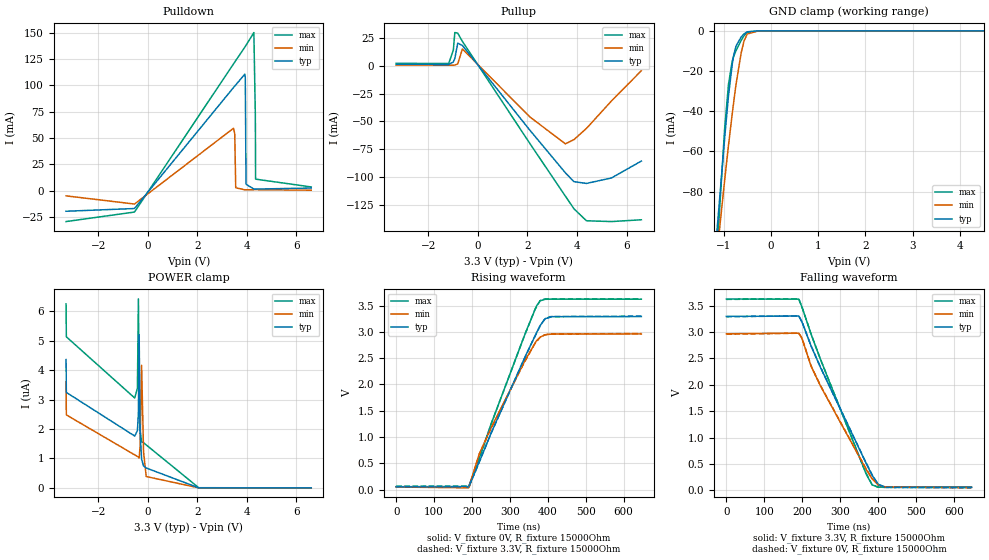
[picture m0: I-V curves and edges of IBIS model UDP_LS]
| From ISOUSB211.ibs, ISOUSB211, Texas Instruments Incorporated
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[Model]   UDP_LS
Model_type   I/O
Polarity   Non-Inverting
Enable   Active-Low
Vinl = 0.8
Vinh = 2
Vmeas = 1.65
Vref = 1.65
Cref = 7pF
Rref = 15000
|   typ   min   max
C_comp   8pF   5pF   10pF
[Voltage Range]   3.3   2.97   3.63
[Temperature Range]   27   150   -40
[Pullup Reference]   3.3   2.97   3.63
[Pulldown Reference]   -0   -0   -0
[Power Clamp Reference]   3.3   2.97   3.63
[GND Clamp Reference]   0   0   0
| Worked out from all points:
|   slope of the pulldown table from 0 to 0.495 V, typ, clamps not added: 33.7 ohm
|   slope of the pullup table from 0 to 0.495 V, typ, clamps not added: 35.8 ohm
|   GND clamp passes 1 mA (typ) near -0.54 V on its own axis
|   falling waveform, V_fixture 3.3V, R_fixture 15000Ohm: 20-80 % time 127ns typ, 128ns min, 116ns max; typ from 3.3 V to 0.057 V
|   rising waveform, V_fixture 0V, R_fixture 15000Ohm: 20-80 % time 119ns typ, 117ns min, 110ns max; typ from 0.05 V to 3.29 V
|   rising waveform, V_fixture 3.3V, R_fixture 15000Ohm: 20-80 % time 119ns typ, 118ns min, 110ns max; typ from 0.057 V to 3.3 V
|   falling waveform, V_fixture 0V, R_fixture 15000Ohm: 20-80 % time 127ns typ, 128ns min, 117ns max; typ from 3.29 V to 0.05 V
[Pulldown]
|   Voltage   I(typ)   I(min)   I(max)
-3.3V     -19.54mA   -4.929mA   -29.33mA
-537.9mV  -16.94mA   -12.7mA    -20.3mA
3.462V    97.95mA    59.28mA    120.4mA
3.511V    99.28mA    54.08mA    122.1mA
3.551V    100.4mA    2.78mA     123.5mA
3.917V    110.6mA    791.1uA    136.2mA
3.937V    107.2mA    798uA      136.9mA
3.967V    6.132mA    808.4uA    138mA
4.283V    1.558mA    916.9uA    150.1mA
4.343V    1.509mA    936.8uA    70.94mA
4.353V    1.513mA    940.1uA    10.95mA
6.6V      2.508mA    452.9uA    3.524mA
[GND Clamp]
|   Voltage   I(typ)   I(min)   I(max)
-3.3V     -1.286A    -1.121A    -1.579A
-1.3V     -145.3mA   -147.2mA   -170.6mA
-973.5mV  -52.59mA   -73.66mA   -47.68mA
-894.3mV  -32.06mA   -56.81mA   -26.49mA
-815.1mV  -16.5mA    -41.06mA   -14.88mA
-785.4mV  -12.23mA   -35.46mA   -12.65mA
-735.9mV  -7.575mA   -26.62mA   -9.853mA
-627mV    -3.033mA   -10.97mA   -4.745mA
-567.6mV  -1.539mA   -5.066mA   -2.489mA
-498.3mV  -471.8uA   -1.571mA   -746.6uA
-260.7mV  0A         -5.306uA   0A
6.6V      0A         0A         0A
[Pullup]
|   Voltage   I(typ)   I(min)   I(max)
-3.3V     1.142mA    462.8uA    2.096mA
-1.181V   1.061mA    442.2uA    1.943mA
-993.3mV  3.404mA    441.8uA    13.88mA
-933.9mV  6.371mA    532.5uA    29.69mA
-815.1mV  20.2mA     1.602mA    29.2mA
-627mV    18.13mA    15.01mA    21.78mA
2.095V    -57.8mA    -45.93mA   -69.71mA
3.531V    -96.08mA   -70.07mA   -117mA
3.877V    -104mA     -66.31mA   -128.3mA
4.382V    -105.6mA   -56.28mA   -139.1mA
5.392V    -100.7mA   -31.65mA   -139.8mA
6.6V      -85.53mA   -4.484mA   -138.2mA
[POWER Clamp]
|   Voltage   I(typ)   I(min)   I(max)
-3.3V     4.356uA    3.599uA    6.246uA
-3.29V    3.241uA    2.478uA    5.13uA
-528mV    1.759uA    1.119uA    3.051uA
-419.1mV  1.943uA    1.069uA    3.389uA
-379.5mV  2.53uA     1.044uA    6.418uA
-349.8mV  5.208uA    1.013uA    3.192uA
-310.2mV  1.899uA    1.42uA     1.946uA
-250.8mV  973.2nA    4.16uA     1.567uA
-171.6mV  741.5nA    1.215uA    1.531uA
-62.7mV   674.3nA    384.4nA    1.457uA
2.056V    0A         0A         4.459nA
6.6V      0A         0A         0A
[Ramp]
R_load = 15000
|   typ   min   max
dV/dt_r   1.94404/1.18803e-07   1.74728/1.17376e-07   2.13944/1.09801e-07
dV/dt_f   1.94431/1.26859e-07   1.74734/1.27745e-07   2.13971/1.1642e-07
[Falling Waveform]
V_fixture = 3.3V
V_fixture_min = 2.97V
V_fixture_max = 3.63V
R_fixture = 15000Ohm
C_fixture = 0F
|   Time   V(typ)   V(min)   V(max)
0s        3.298V     2.968V     3.627V
191.1ns   3.304V     2.98V      3.625V
199.7ns   3.189V     2.877V     3.472V
223.7ns   2.734V     2.351V     2.958V
248ns     2.335V     1.983V     2.49V
369.6ns   501mV      386.8mV    297.9mV
384.7ns   285.7mV    216.3mV    103.3mV
400.7ns   112.8mV    101.1mV    61.56mV
419.8ns   59.09mV    64.55mV    61.44mV
646.7ns   57.28mV    56mV       61.04mV
[Rising Waveform]
V_fixture = 0V
V_fixture_min = 0V
V_fixture_max = 0V
R_fixture = 15000Ohm
C_fixture = 0F
|   Time   V(typ)   V(min)   V(max)
0s        49.91mV    47.52mV    54.29mV
191.1ns   46.69mV    31.65mV    55.44mV
219ns     523.2mV    674.9mV    589.8mV
249.7ns   1.064V     1.165V     1.233V
341.4ns   2.547V     2.475V     2.986V
369.6ns   2.974V     2.825V     3.485V
379.6ns   3.119V     2.899V     3.591V
393.2ns   3.251V     2.945V     3.619V
411.8ns   3.289V     2.958V     3.621V
646.7ns   3.29V      2.96V      3.62V
[Rising Waveform]
V_fixture = 3.3V
V_fixture_min = 2.97V
V_fixture_max = 3.63V
R_fixture = 15000Ohm
C_fixture = 0F
|   Time   V(typ)   V(min)   V(max)
0s        57.28mV    56mV       61.04mV
192.3ns   59.23mV    43.25mV    63.05mV
219ns     518.2mV    668.7mV    587.9mV
249.7ns   1.058V     1.156V     1.232V
334.3ns   2.431V     2.369V     2.854V
365.8ns   2.911V     2.776V     3.42V
379.6ns   3.113V     2.894V     3.592V
391ns     3.235V     2.939V     3.625V
405.6ns   3.289V     2.958V     3.626V
646.7ns   3.298V     2.968V     3.627V
[Falling Waveform]
|Gnd
V_fixture = 0V
V_fixture_min = 0V
V_fixture_max = 0V
R_fixture = 15000Ohm
C_fixture = 0F
|   Time   V(typ)   V(min)   V(max)
0s        3.29V      2.96V      3.62V
191.1ns   3.308V     2.979V     3.63V
199.7ns   3.195V     2.882V     3.474V
223.7ns   2.737V     2.357V     2.96V
248ns     2.342V     1.992V     2.492V
365.8ns   564.5mV    444.8mV    366mV
384.7ns   290.9mV    224.8mV    103.8mV
400.7ns   115.6mV    105.6mV    59.55mV
419.8ns   55.91mV    62.81mV    55.52mV
646.7ns   49.91mV    47.52mV    54.29mV
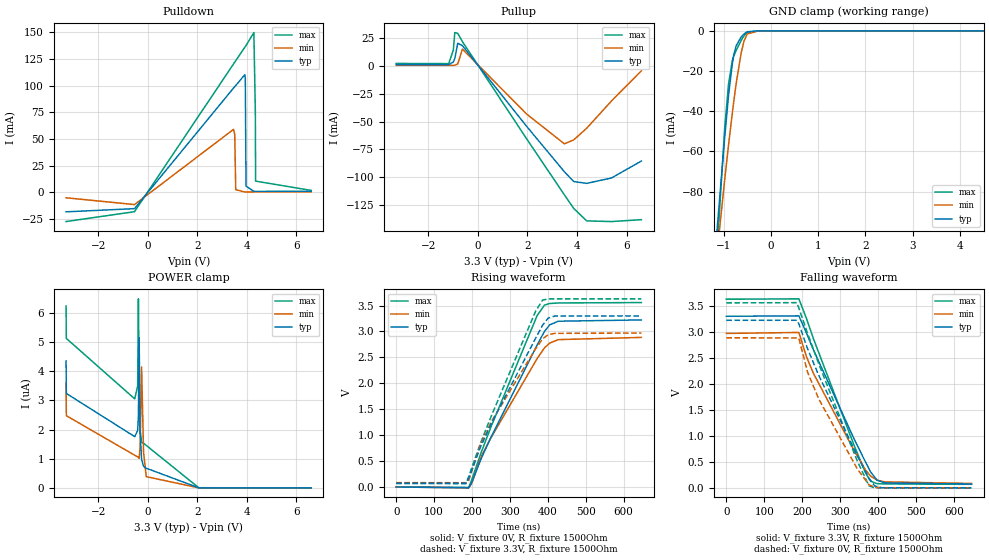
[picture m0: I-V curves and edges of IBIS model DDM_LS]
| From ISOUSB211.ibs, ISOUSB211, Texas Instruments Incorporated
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[Model]   DDM_LS
Model_type   I/O
Polarity   Non-Inverting
Enable   Active-Low
Vinl = 0.8
Vinh = 2
Vmeas = 1.65
Vref = 1.65
Cref = 7pF
Rref = 15000
|   typ   min   max
C_comp   8pF   5pF   10pF
[Voltage Range]   3.3   2.97   3.63
[Temperature Range]   27   150   -40
[Pullup Reference]   3.3   2.97   3.63
[Pulldown Reference]   -0   0   -0
[Power Clamp Reference]   3.3   2.97   3.63
[GND Clamp Reference]   0   0   0
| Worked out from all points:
|   slope of the pulldown table from 0 to 0.495 V, typ, clamps not added: 34.2 ohm
|   slope of the pullup table from 0 to 0.495 V, typ, clamps not added: 35.8 ohm
|   GND clamp passes 1 mA (typ) near -0.54 V on its own axis
|   falling waveform, V_fixture 3.3V, R_fixture 1500Ohm: 20-80 % time 122ns typ, 123ns min, 112ns max; typ from 3.3 V to 0.073 V
|   rising waveform, V_fixture 0V, R_fixture 1500Ohm: 20-80 % time 130ns typ, 134ns min, 118ns max; typ from 0 V to 3.22 V
|   rising waveform, V_fixture 3.3V, R_fixture 1500Ohm: 20-80 % time 133ns typ, 130ns min, 121ns max; typ from 0.073 V to 3.3 V
|   falling waveform, V_fixture 0V, R_fixture 1500Ohm: 20-80 % time 124ns typ, 118ns min, 114ns max; typ from 3.22 V to 0 V
[Pulldown]
|   Voltage   I(typ)   I(min)   I(max)
-3.3V     -18.2mA    -5.021mA   -27.31mA
-537.9mV  -15.2mA    -11.4mA    -18.05mA
3.462V    97.83mA    59.09mA    120.4mA
3.511V    99.15mA    54.21mA    122.1mA
3.551V    100.2mA    2.553mA    123.5mA
3.917V    110.3mA    416.7uA    136mA
3.937V    107.1mA    416.7uA    136.7mA
3.967V    5.835mA    416.7uA    137.7mA
4.283V    1.082mA    416.8uA    149.8mA
4.343V    991.9uA    416.8uA    75.26mA
4.353V    991.9uA    416.8uA    10.57mA
6.6V      1.045mA    453uA      1.865mA
[GND Clamp]
|   Voltage   I(typ)   I(min)   I(max)
-3.3V     -1.286A    -1.12A     -1.579A
-1.3V     -145.3mA   -147.2mA   -170.6mA
-973.5mV  -52.59mA   -73.66mA   -47.69mA
-894.3mV  -32.06mA   -56.82mA   -26.49mA
-815.1mV  -16.5mA    -41.06mA   -14.88mA
-785.4mV  -12.23mA   -35.46mA   -12.65mA
-735.9mV  -7.575mA   -26.62mA   -9.854mA
-627mV    -3.033mA   -10.97mA   -4.745mA
-567.6mV  -1.539mA   -5.066mA   -2.489mA
-498.3mV  -471.8uA   -1.572mA   -746.7uA
-260.7mV  0A         -5.306uA   0A
6.6V      0A         0A         0A
[Pullup]
|   Voltage   I(typ)   I(min)   I(max)
-3.3V     1.143mA    463.2uA    2.098mA
-1.181V   1.062mA    442.5uA    1.976mA
-993.3mV  3.479mA    442.1uA    14.08mA
-933.9mV  6.461mA    534.8uA    29.84mA
-815.1mV  20.25mA    1.633mA    29.15mA
-627mV    18.1mA     14.99mA    21.73mA
1.957V    -54.06mA   -43.1mA    -65.18mA
3.491V    -95.07mA   -70.04mA   -115.8mA
3.868V    -103.9mA   -66.47mA   -128mA
4.392V    -105.5mA   -56.05mA   -139.2mA
5.392V    -100.7mA   -31.61mA   -139.8mA
6.6V      -85.45mA   -4.491mA   -138.1mA
[POWER Clamp]
|   Voltage   I(typ)   I(min)   I(max)
-3.3V     4.356uA    3.599uA    6.245uA
-3.29V    3.24uA     2.477uA    5.129uA
-528mV    1.757uA    1.119uA    3.054uA
-409.2mV  1.968uA    1.064uA    3.496uA
-379.5mV  2.484uA    1.044uA    6.487uA
-349.8mV  5.156uA    1.012uA    3.244uA
-310.2mV  1.922uA    1.418uA    1.96uA
-250.8mV  977.8nA    4.148uA    1.565uA
-171.6mV  739.8nA    1.22uA     1.531uA
-62.7mV   674.2nA    384.7nA    1.457uA
2.056V    0A         0A         4.44nA
6.6V      0A         0A         0A
[Ramp]
R_load = 1500
|   typ   min   max
dV/dt_r   1.93315/1.30202e-07   1.73109/1.34063e-07   2.13437/1.18482e-07
dV/dt_f   1.93521/1.22049e-07   1.73101/1.23353e-07   2.13644/1.11725e-07
[Falling Waveform]
V_fixture = 3.3V
V_fixture_min = 2.97V
V_fixture_max = 3.63V
R_fixture = 1500Ohm
C_fixture = 0F
|   Time   V(typ)   V(min)   V(max)
0s        3.299V     2.969V     3.628V
191.3ns   3.307V     2.988V     3.634V
211.3ns   2.979V     2.523V     3.26V
229.4ns   2.659V     2.207V     2.875V
337.2ns   937.5mV    714.8mV    812.7mV
367.2ns   495.1mV    343.8mV    286.9mV
380.6ns   305mV      224.8mV    126.7mV
397.6ns   146.1mV    148.1mV    80.38mV
417.8ns   94.49mV    114.6mV    74.54mV
646.7ns   73.38mV    83.97mV    67.42mV
[Rising Waveform]
V_fixture = 0V
V_fixture_min = 0V
V_fixture_max = 0V
R_fixture = 1500Ohm
C_fixture = 0F
|   Time   V(typ)   V(min)   V(max)
0s        7.209nV    274.9nV    6.38nV
191.3ns   -16.21mV   -16.46mV   -7.616mV
199.1ns   84.02mV    64.94mV    138.4mV
224.3ns   551.5mV    589.6mV    669.9mV
249.2ns   945.7mV    940.3mV    1.144V
371.6ns   2.737V     2.475V     3.303V
391.1ns   3V         2.683V     3.508V
404.8ns   3.127V     2.775V     3.538V
427.6ns   3.197V     2.842V     3.549V
646.7ns   3.222V     2.885V     3.557V
[Rising Waveform]
V_fixture = 3.3V
V_fixture_min = 2.97V
V_fixture_max = 3.63V
R_fixture = 1500Ohm
C_fixture = 0F
|   Time   V(typ)   V(min)   V(max)
0s        73.38mV    83.94mV    67.42mV
184.2ns   73.41mV    82.37mV    63.66mV
191ns     166.5mV    121mV      198.8mV
221.9ns   762mV      806.5mV    835.8mV
251ns     1.227V     1.261V     1.371V
367.2ns   2.861V     2.66V      3.382V
386.1ns   3.119V     2.855V     3.604V
400.5ns   3.255V     2.935V     3.627V
417.8ns   3.297V     2.963V     3.628V
646.7ns   3.299V     2.969V     3.628V
[Falling Waveform]
|Gnd
V_fixture = 0V
V_fixture_min = 0V
V_fixture_max = 0V
R_fixture = 1500Ohm
C_fixture = 0F
|   Time   V(typ)   V(min)   V(max)
0s        3.222V     2.885V     3.557V
186ns     3.222V     2.883V     3.561V
191.3ns   3.154V     2.876V     3.455V
214.5ns   2.671V     2.22V      2.966V
244ns     2.159V     1.706V     2.38V
345.3ns   623.2mV    366.6mV    518.1mV
376.2ns   182.6mV    58.28mV    37.7mV
391.5ns   35.42mV    11.2mV     -521.7uV
410.5ns   865.8uV    1.756mV    -482.9uV
646.7ns   35.26nV    -1.726uV   59.6nV
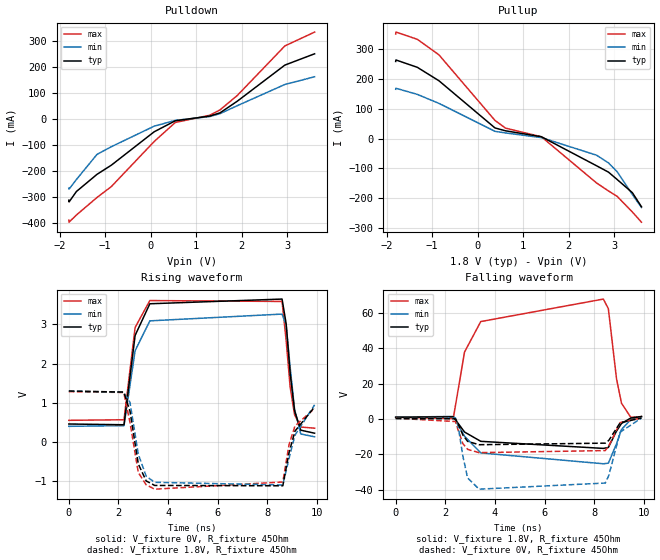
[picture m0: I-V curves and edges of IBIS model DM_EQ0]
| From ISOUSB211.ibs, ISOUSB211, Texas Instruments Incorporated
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[Model]   DM_EQ0
Model_type   Output
Polarity   Inverting
Vmeas = 0.2
Vref = 0
Cref = 15pF
Rref = 45
|   typ   min   max
C_comp   5pF   3pF   8pF
[Voltage Range]   1.8   1.71   1.89
[Temperature Range]   27   150   -40
[Pullup Reference]   1.8   1.71   1.89
[Pulldown Reference]   0   0   0
[Power Clamp Reference]   1.8   1.71   1.89
[GND Clamp Reference]   0   0   0
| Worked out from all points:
|   slope of the pulldown table from 0 to 0.27 V, typ, clamps not added: 7.95 ohm
|   slope of the pullup table from 0 to 0.27 V, typ, clamps not added: 7.94 ohm
|   falling waveform, V_fixture 1.8V, R_fixture 45Ohm: 20-80 % time 125ps typ, 1.14ns min, 7.56ps max; typ from 0.895 V to 1.3 V
|   rising waveform, V_fixture 0V, R_fixture 45Ohm: 20-80 % time 129ps typ, 110ps min, 129ps max; typ from 0.46 V to 0.225 V
|   rising waveform, V_fixture 1.8V, R_fixture 45Ohm: 20-80 % time 105ps typ, 111ps min, 98.2ps max; typ from 1.3 V to 0.895 V
|   falling waveform, V_fixture 0V, R_fixture 45Ohm: 20-80 % time 88.5ps typ, 1.17ns min, 103ps max; typ from 0.225 V to 0.46 V
[Pulldown]
|   Voltage   I(typ)   I(min)   I(max)
-1.8V     -312.3mA   -266.2mA   -388.8mA
-1.795V   -319mA     -269.8mA   -396.8mA
-1.633V   -278.9mA   -232.8mA   -369.2mA
-1.179V   -212.7mA   -136mA     -301.6mA
-865.8mV  -177.8mA   -106.8mA   -260mA
73.8mV    -49.63mA   -27.98mA   -87.09mA
538.2mV   -7.266mA   -5.626mA   -13.71mA
1.294V    10.85mA    9.019mA    13.98mA
1.521V    23.18mA    20.15mA    34.45mA
1.899V    67.71mA    50.57mA    89.7mA
2.947V    206.8mA    132.3mA    280.4mA
3.6V      250.2mA    161.9mA    333.6mA
[Pullup]
|   Voltage   I(typ)   I(min)   I(max)
-1.8V     259.8mA    166.3mA    352.1mA
-1.795V   264.8mA    169.7mA    358.5mA
-1.325V   240.1mA    149.1mA    334.3mA
-849.6mV  194.9mA    118.9mA    282mA
381.6mV   36.3mA     24.84mA    61.51mA
613.8mV   26.64mA    19.55mA    35.63mA
1.402V    6.733mA    3.773mA    6.537mA
2.612V    -90.76mA   -55.24mA   -148.5mA
2.876V    -112.3mA   -81.28mA   -175.5mA
3.065V    -136.9mA   -110.7mA   -193.6mA
3.4V      -181.3mA   -187.3mA   -246.2mA
3.6V      -228.6mA   -231.2mA   -280.5mA
[Ramp]
R_load = 45
|   typ   min   max
dV/dt_r   0.140808/4.09327e-09   0.160407/6.33884e-10   0.120509/4.73283e-09
dV/dt_f   0.243789/7.60429e-09   0.210518/4.8172e-10   0.256824/1.17719e-09
[Falling Waveform]
V_fixture = 1.8V
V_fixture_min = 1.71V
V_fixture_max = 1.89V
R_fixture = 45Ohm
C_fixture = 0F
|   Time   V(typ)   V(min)   V(max)
0s        895mV      947.6mV    856.5mV
2.319ns   1.148V     1.375V     200.3mV
2.774ns   -7.476V    -9.881V    37.87V
3.427ns   -12.73V    -19.28V    55.08V
8.364ns   -16.73V    -25.43V    67.82V
8.566ns   -16.2V     -25.09V    62.41V
8.894ns   -6.968V    -14.2V     22.79V
9.095ns   -2.617V    -6.029V    8.889V
9.471ns   465.5mV    -380.6mV   833.3mV
9.9ns     1.301V     1.298V     1.285V
[Rising Waveform]
V_fixture = 0V
V_fixture_min = 0V
V_fixture_max = 0V
R_fixture = 45Ohm
C_fixture = 0F
|   Time   V(typ)   V(min)   V(max)
0s        459.5mV    400.3mV    553.4mV
2.223ns   440.3mV    417mV      568.1mV
2.671ns   2.72V      2.331V     2.923V
3.264ns   3.527V     3.091V     3.609V
8.59ns    3.647V     3.264V     3.586V
8.755ns   3.015V     2.982V     2.587V
8.916ns   1.752V     1.907V     1.399V
9.095ns   795.7mV    828mV      695.8mV
9.343ns   301.7mV    204.8mV    382.4mV
9.9ns     224.9mV    133mV      352.5mV
[Rising Waveform]
V_fixture = 1.8V
V_fixture_min = 1.71V
V_fixture_max = 1.89V
R_fixture = 45Ohm
C_fixture = 0F
|   Time   V(typ)   V(min)   V(max)
0s        1.301V     1.298V     1.285V
2.213ns   1.274V     1.27V      1.264V
2.463ns   790.2mV    1.013V     501.7mV
2.799ns   -558.9mV   -310.2mV   -778.1mV
3.116ns   -992.4mV   -871.7mV   -1.093V
3.459ns   -1.108V    -1.028V    -1.203V
8.62ns    -1.117V    -1.097V    -1.02V
8.872ns   -268.8mV   -416.8mV   -66.48mV
9.11ns    277.5mV    175.1mV    409.6mV
9.9ns     895mV      947.6mV    856.5mV
[Falling Waveform]
|Gnd
V_fixture = 0V
V_fixture_min = 0V
V_fixture_max = 0V
R_fixture = 45Ohm
C_fixture = 0F
|   Time   V(typ)   V(min)   V(max)
0s        224.9mV    133mV      352.5mV
2.408ns   32.21mV    463.5mV    -1.531V
2.514ns   -2.726V    -3.994V    -6.257V
2.708ns   -9.186V    -21.28V    -14.11V
2.897ns   -12.74V    -33.43V    -17.26V
3.357ns   -14.64V    -39.81V    -19.14V
8.443ns   -13.76V    -36.33V    -17.96V
8.584ns   -12.19V    -32.1V     -15.25V
9.04ns    -2.253V    -7.509V    -2.142V
9.9ns     459.5mV    400.3mV    553.4mV
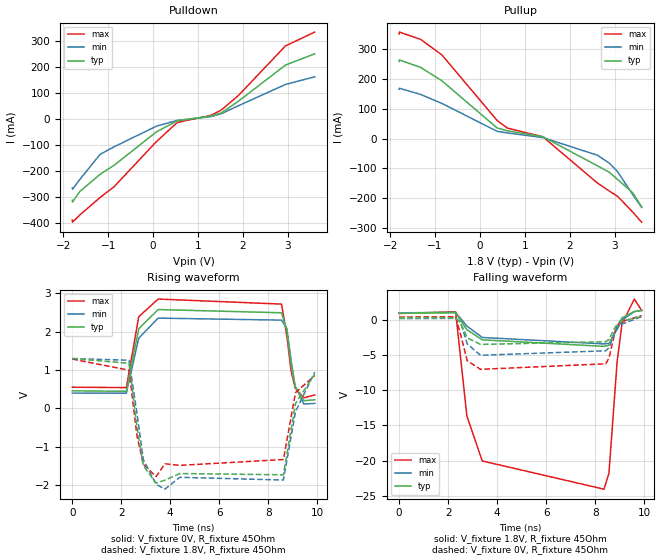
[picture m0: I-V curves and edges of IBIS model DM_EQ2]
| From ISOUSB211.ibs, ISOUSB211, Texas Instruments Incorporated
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[Model]   DM_EQ2
Model_type   Output
Polarity   Inverting
Vmeas = 0.2
Vref = 0
Cref = 15pF
Rref = 45
|   typ   min   max
C_comp   5pF   3pF   8pF
[Voltage Range]   1.8   1.71   1.89
[Temperature Range]   27   150   -40
[Pullup Reference]   1.8   1.71   1.89
[Pulldown Reference]   0   0   0
[Power Clamp Reference]   1.8   1.71   1.89
[GND Clamp Reference]   0   0   0
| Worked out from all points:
|   slope of the pulldown table from 0 to 0.27 V, typ, clamps not added: 7.95 ohm
|   slope of the pullup table from 0 to 0.27 V, typ, clamps not added: 7.94 ohm
|   falling waveform, V_fixture 1.8V, R_fixture 45Ohm: 20-80 % time 353ps typ, 320ps min, 30.5ps max; typ from 0.895 V to 1.3 V
|   rising waveform, V_fixture 0V, R_fixture 45Ohm: 20-80 % time 134ps typ, 143ps min, 99.3ps max; typ from 0.46 V to 0.225 V
|   rising waveform, V_fixture 1.8V, R_fixture 45Ohm: 20-80 % time 90.1ps typ, 93.9ps min, 89ps max; typ from 1.3 V to 0.895 V
|   falling waveform, V_fixture 0V, R_fixture 45Ohm: 20-80 % time 361ps typ, 262ps min, 73.4ps max; typ from 0.225 V to 0.46 V
[Pulldown]
|   Voltage   I(typ)   I(min)   I(max)
-1.8V     -312.3mA   -266.2mA   -388.8mA
-1.795V   -319mA     -269.8mA   -396.8mA
-1.633V   -278.9mA   -232.8mA   -369.2mA
-1.179V   -212.7mA   -136mA     -301.6mA
-865.8mV  -177.8mA   -106.8mA   -260mA
73.8mV    -49.63mA   -27.98mA   -87.09mA
538.2mV   -7.266mA   -5.626mA   -13.71mA
1.294V    10.85mA    9.019mA    13.98mA
1.521V    23.18mA    20.15mA    34.45mA
1.899V    67.71mA    50.57mA    89.7mA
2.947V    206.8mA    132.3mA    280.4mA
3.6V      250.2mA    161.9mA    333.6mA
[Pullup]
|   Voltage   I(typ)   I(min)   I(max)
-1.8V     259.8mA    166.3mA    352.1mA
-1.795V   264.8mA    169.7mA    358.5mA
-1.325V   240.1mA    149.1mA    334.3mA
-849.6mV  194.9mA    118.9mA    282mA
381.6mV   36.3mA     24.84mA    61.51mA
613.8mV   26.64mA    19.55mA    35.63mA
1.402V    6.733mA    3.773mA    6.537mA
2.612V    -90.76mA   -55.24mA   -148.5mA
2.876V    -112.3mA   -81.28mA   -175.5mA
3.065V    -136.9mA   -110.7mA   -193.6mA
3.4V      -181.3mA   -187.3mA   -246.2mA
3.6V      -228.6mA   -231.2mA   -280.5mA
[Ramp]
R_load = 45
|   typ   min   max
dV/dt_r   0.140808/1.22024e-10   0.160407/1.24474e-10   0.120509/2.76295e-09
dV/dt_f   0.243789/6.46796e-09   0.210518/7.33042e-09   0.256824/2.32055e-09
[Falling Waveform]
V_fixture = 1.8V
V_fixture_min = 1.71V
V_fixture_max = 1.89V
R_fixture = 45Ohm
C_fixture = 0F
|   Time   V(typ)   V(min)   V(max)
0s        895mV      947.6mV    856.5mV
2.306ns   953.6mV    1.013V     1.095V
2.765ns   -1.439V    -927.1mV   -13.67V
3.392ns   -2.877V    -2.544V    -20.05V
8.363ns   -3.806V    -3.455V    -24.05V
8.565ns   -3.65V     -3.392V    -21.81V
8.901ns   -966.5mV   -1.345V    -5.908V
9.1ns     235.9mV    -56.67mV   -596.6mV
9.602ns   1.143V     1.103V     2.9V
9.9ns     1.301V     1.298V     1.285V
[Rising Waveform]
V_fixture = 0V
V_fixture_min = 0V
V_fixture_max = 0V
R_fixture = 45Ohm
C_fixture = 0F
|   Time   V(typ)   V(min)   V(max)
0s        459.5mV    400.3mV    553.4mV
2.207ns   446.7mV    396.1mV    542.9mV
2.713ns   2.076V     1.829V     2.386V
3.504ns   2.574V     2.351V     2.847V
8.545ns   2.49V      2.299V     2.716V
8.758ns   2.047V     2.083V     1.898V
8.934ns   1.145V     1.258V     978.9mV
9.1ns     557mV      579.1mV    531.5mV
9.456ns   202.5mV    114.7mV    277.2mV
9.9ns     224.9mV    133mV      352.5mV
[Rising Waveform]
V_fixture = 1.8V
V_fixture_min = 1.71V
V_fixture_max = 1.89V
R_fixture = 45Ohm
C_fixture = 0F
|   Time   V(typ)   V(min)   V(max)
0s        1.301V     1.298V     1.285V
2.317ns   1.175V     1.256V     995.8mV
2.64ns    -467.5mV   -126.4mV   -702.6mV
2.901ns   -1.49V     -1.332V    -1.453V
3.421ns   -1.94V     -1.971V    -1.772V
3.783ns   -1.867V    -2.1V      -1.441V
4.388ns   -1.693V    -1.792V    -1.481V
8.62ns    -1.726V    -1.862V    -1.328V
9.115ns   132.7mV    -78.84mV   413.1mV
9.9ns     895mV      947.6mV    856.5mV
[Falling Waveform]
|Gnd
V_fixture = 0V
V_fixture_min = 0V
V_fixture_max = 0V
R_fixture = 45Ohm
C_fixture = 0F
|   Time   V(typ)   V(min)   V(max)
0s        224.9mV    133mV      352.5mV
2.302ns   250.2mV    161.9mV    384.4mV
2.503ns   -457mV     -372mV     -2.039V
2.779ns   -2.584V    -3.458V    -5.834V
3.32ns    -3.529V    -5.067V    -7.062V
8.436ns   -3.152V    -4.436V    -6.279V
8.565ns   -2.821V    -3.994V    -5.494V
8.819ns   -1.06V     -1.77V     -1.703V
9.004ns   -324.5mV   -775.9mV   -395.2mV
9.9ns     459.5mV    400.3mV    553.4mV
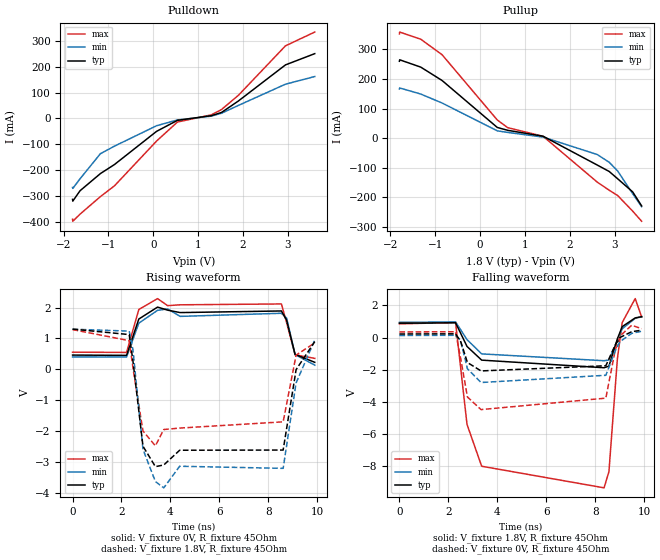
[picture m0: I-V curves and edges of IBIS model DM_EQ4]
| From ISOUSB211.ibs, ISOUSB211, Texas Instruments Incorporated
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[Model]   DM_EQ4
Model_type   Output
Polarity   Inverting
Vmeas = 0.2
Vref = 0
Cref = 15pF
Rref = 45
|   typ   min   max
C_comp   5pF   3pF   8pF
[Voltage Range]   1.8   1.71   1.89
[Temperature Range]   27   150   -40
[Pullup Reference]   1.8   1.71   1.89
[Pulldown Reference]   0   0   0
[Power Clamp Reference]   1.8   1.71   1.89
[GND Clamp Reference]   0   0   0
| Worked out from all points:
|   slope of the pulldown table from 0 to 0.27 V, typ, clamps not added: 7.95 ohm
|   slope of the pullup table from 0 to 0.27 V, typ, clamps not added: 7.94 ohm
|   falling waveform, V_fixture 1.8V, R_fixture 45Ohm: 20-80 % time 344ps typ, 347ps min, 42.2ps max; typ from 0.895 V to 1.3 V
|   rising waveform, V_fixture 0V, R_fixture 45Ohm: 20-80 % time 162ps typ, 173ps min, 102ps max; typ from 0.46 V to 0.225 V
|   rising waveform, V_fixture 1.8V, R_fixture 45Ohm: 20-80 % time 79ps typ, 76.1ps min, 80.7ps max; typ from 1.3 V to 0.895 V
|   falling waveform, V_fixture 0V, R_fixture 45Ohm: 20-80 % time 393ps typ, 397ps min, 60ps max; typ from 0.225 V to 0.46 V
[Pulldown]
|   Voltage   I(typ)   I(min)   I(max)
-1.8V     -312.3mA   -266.2mA   -388.8mA
-1.795V   -319mA     -269.8mA   -396.8mA
-1.633V   -278.9mA   -232.8mA   -369.2mA
-1.179V   -212.7mA   -136mA     -301.6mA
-865.8mV  -177.8mA   -106.8mA   -260mA
73.8mV    -49.63mA   -27.98mA   -87.09mA
538.2mV   -7.266mA   -5.626mA   -13.71mA
1.294V    10.85mA    9.019mA    13.98mA
1.521V    23.18mA    20.15mA    34.45mA
1.899V    67.71mA    50.57mA    89.7mA
2.947V    206.8mA    132.3mA    280.4mA
3.6V      250.2mA    161.9mA    333.6mA
[Pullup]
|   Voltage   I(typ)   I(min)   I(max)
-1.8V     259.8mA    166.3mA    352.1mA
-1.795V   264.8mA    169.7mA    358.5mA
-1.325V   240.1mA    149.1mA    334.3mA
-849.6mV  194.9mA    118.9mA    282mA
381.6mV   36.3mA     24.84mA    61.51mA
613.8mV   26.64mA    19.55mA    35.63mA
1.402V    6.733mA    3.773mA    6.537mA
2.612V    -90.76mA   -55.24mA   -148.5mA
2.876V    -112.3mA   -81.28mA   -175.5mA
3.065V    -136.9mA   -110.7mA   -193.6mA
3.4V      -181.3mA   -187.3mA   -246.2mA
3.6V      -228.6mA   -231.2mA   -280.5mA
[Ramp]
R_load = 45
|   typ   min   max
dV/dt_r   0.140808/1.40091e-10   0.160407/1.42554e-10   0.120509/1.03038e-10
dV/dt_f   0.243789/2.87975e-10   0.210518/3.05841e-10   0.256824/6.92704e-09
[Falling Waveform]
V_fixture = 1.8V
V_fixture_min = 1.71V
V_fixture_max = 1.89V
R_fixture = 45Ohm
C_fixture = 0F
|   Time   V(typ)   V(min)   V(max)
0s        895mV      947.6mV    856.5mV
2.295ns   922.1mV    976.4mV    936.6mV
2.762ns   -547.4mV   -123.4mV   -5.391V
3.361ns   -1.399V    -1.011V    -7.991V
8.364ns   -1.871V    -1.435V    -9.333V
8.563ns   -1.773V    -1.393V    -8.329V
8.908ns   -75.42mV   -191.3mV   -1.328V
9.107ns   682.5mV    548.2mV    938.1mV
9.636ns   1.224V     1.198V     2.424V
9.9ns     1.301V     1.298V     1.285V
[Rising Waveform]
V_fixture = 0V
V_fixture_min = 0V
V_fixture_max = 0V
R_fixture = 45Ohm
C_fixture = 0F
|   Time   V(typ)   V(min)   V(max)
0s        459.5mV    400.3mV    553.4mV
2.207ns   450.5mV    397.2mV    546mV
2.708ns   1.627V     1.494V     1.936V
3.475ns   2.014V     1.91V      2.289V
3.885ns   1.915V     1.954V     2.061V
4.401ns   1.836V     1.713V     2.088V
8.537ns   1.889V     1.814V     2.116V
8.75ns    1.589V     1.656V     1.51V
9.095ns   482.9mV    475.7mV    468.1mV
9.9ns     224.9mV    133mV      352.5mV
[Rising Waveform]
V_fixture = 1.8V
V_fixture_min = 1.71V
V_fixture_max = 1.89V
R_fixture = 45Ohm
C_fixture = 0F
|   Time   V(typ)   V(min)   V(max)
0s        1.301V     1.298V     1.285V
2.315ns   1.124V     1.236V     927mV
2.47ns    258.7mV    619.8mV    38.13mV
2.878ns   -2.492V    -2.594V    -1.999V
3.385ns   -3.154V    -3.637V    -2.481V
3.728ns   -3.101V    -3.841V    -1.952V
4.378ns   -2.623V    -3.142V    -1.905V
8.608ns   -2.617V    -3.21V     -1.703V
9.137ns   -11.84mV   -441.3mV   456.7mV
9.9ns     895mV      947.6mV    856.5mV
[Falling Waveform]
|Gnd
V_fixture = 0V
V_fixture_min = 0V
V_fixture_max = 0V
R_fixture = 45Ohm
C_fixture = 0F
|   Time   V(typ)   V(min)   V(max)
0s        224.9mV    133mV      352.5mV
2.291ns   234.9mV    144.6mV    363.9mV
2.496ns   -206mV     -176mV     -1.234V
2.78ns    -1.55V     -1.937V    -3.691V
3.336ns   -2.069V    -2.789V    -4.472V
8.436ns   -1.748V    -2.34V     -3.76V
8.821ns   -457.4mV   -822.9mV   -774.3mV
9.016ns   8.887mV    -245.1mV   102.3mV
9.495ns   369.8mV    261.8mV    767.6mV
9.9ns     459.5mV    400.3mV    553.4mV
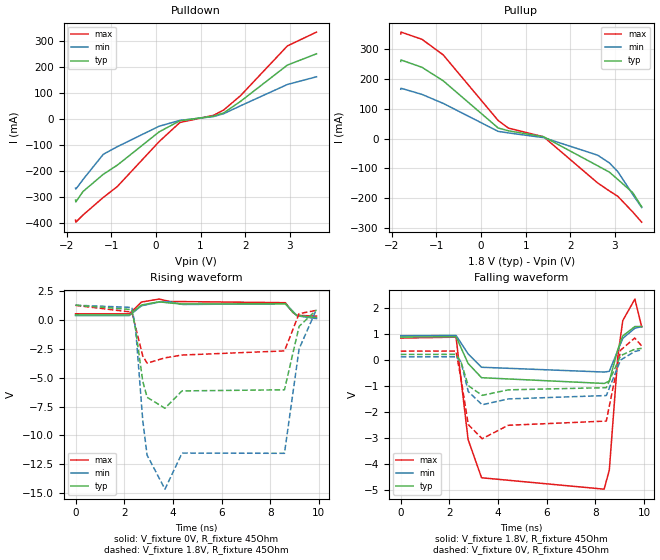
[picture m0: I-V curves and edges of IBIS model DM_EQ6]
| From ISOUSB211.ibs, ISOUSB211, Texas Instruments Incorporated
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[Model]   DM_EQ6
Model_type   Output
Polarity   Inverting
Vmeas = 0.2
Vref = 0
Cref = 15pF
Rref = 45
|   typ   min   max
C_comp   5pF   3pF   8pF
[Voltage Range]   1.8   1.71   1.89
[Temperature Range]   27   150   -40
[Pullup Reference]   1.8   1.71   1.89
[Pulldown Reference]   0   0   0
[Power Clamp Reference]   1.8   1.71   1.89
[GND Clamp Reference]   0   0   0
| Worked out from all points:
|   slope of the pulldown table from 0 to 0.27 V, typ, clamps not added: 7.95 ohm
|   slope of the pullup table from 0 to 0.27 V, typ, clamps not added: 7.94 ohm
|   falling waveform, V_fixture 1.8V, R_fixture 45Ohm: 20-80 % time 278ps typ, 368ps min, 46.9ps max; typ from 0.895 V to 1.3 V
|   rising waveform, V_fixture 0V, R_fixture 45Ohm: 20-80 % time 205ps typ, 207ps min, 115ps max; typ from 0.46 V to 0.225 V
|   rising waveform, V_fixture 1.8V, R_fixture 45Ohm: 20-80 % time 220ps typ, 96.7ps min, 53.4ps max; typ from 1.3 V to 0.895 V
|   falling waveform, V_fixture 0V, R_fixture 45Ohm: 20-80 % time 334ps typ, 403ps min, 68.7ps max; typ from 0.225 V to 0.46 V
[Pulldown]
|   Voltage   I(typ)   I(min)   I(max)
-1.8V     -312.3mA   -266.2mA   -388.8mA
-1.795V   -319mA     -269.8mA   -396.8mA
-1.633V   -278.9mA   -232.8mA   -369.2mA
-1.179V   -212.7mA   -136mA     -301.6mA
-865.8mV  -177.8mA   -106.8mA   -260mA
73.8mV    -49.63mA   -27.98mA   -87.09mA
538.2mV   -7.266mA   -5.626mA   -13.71mA
1.294V    10.85mA    9.019mA    13.98mA
1.521V    23.18mA    20.15mA    34.45mA
1.899V    67.71mA    50.57mA    89.7mA
2.947V    206.8mA    132.3mA    280.4mA
3.6V      250.2mA    161.9mA    333.6mA
[Pullup]
|   Voltage   I(typ)   I(min)   I(max)
-1.8V     259.8mA    166.3mA    352.1mA
-1.795V   264.8mA    169.7mA    358.5mA
-1.325V   240.1mA    149.1mA    334.3mA
-849.6mV  194.9mA    118.9mA    282mA
381.6mV   36.3mA     24.84mA    61.51mA
613.8mV   26.64mA    19.55mA    35.63mA
1.402V    6.733mA    3.773mA    6.537mA
2.612V    -90.76mA   -55.24mA   -148.5mA
2.876V    -112.3mA   -81.28mA   -175.5mA
3.065V    -136.9mA   -110.7mA   -193.6mA
3.4V      -181.3mA   -187.3mA   -246.2mA
3.6V      -228.6mA   -231.2mA   -280.5mA
[Ramp]
R_load = 45
|   typ   min   max
dV/dt_r   0.140808/1.68279e-10   0.160407/1.68504e-10   0.120509/1.15755e-10
dV/dt_f   0.243789/2.53076e-10   0.210518/3.26489e-10   0.256824/2.68335e-09
[Falling Waveform]
V_fixture = 1.8V
V_fixture_min = 1.71V
V_fixture_max = 1.89V
R_fixture = 45Ohm
C_fixture = 0F
|   Time   V(typ)   V(min)   V(max)
0s        895mV      947.6mV    856.5mV
2.271ns   909.2mV    959.2mV    891mV
2.767ns   -120.9mV   247.6mV    -3.053V
3.32ns    -671.1mV   -268.4mV   -4.527V
8.356ns   -892.1mV   -453.4mV   -4.966V
8.569ns   -804.6mV   -425.2mV   -4.232V
8.92ns    418.6mV    380.7mV    152.8mV
9.122ns   939.3mV    844.7mV    1.529V
9.62ns    1.3V       1.234V     2.359V
9.9ns     1.301V     1.298V     1.285V
[Rising Waveform]
V_fixture = 0V
V_fixture_min = 0V
V_fixture_max = 0V
R_fixture = 45Ohm
C_fixture = 0F
|   Time   V(typ)   V(min)   V(max)
0s        459.5mV    400.3mV    553.4mV
2.207ns   453.6mV    398.1mV    548.6mV
2.708ns   1.316V     1.25V      1.572V
3.43ns    1.595V     1.569V     1.831V
3.896ns   1.482V     1.582V     1.61V
4.4ns     1.406V     1.361V     1.612V
8.62ns    1.421V     1.428V     1.516V
8.92ns    713mV      796.5mV    674.8mV
9.094ns   409.5mV    380.7mV    419.9mV
9.9ns     224.9mV    133mV      352.5mV
[Rising Waveform]
V_fixture = 1.8V
V_fixture_min = 1.71V
V_fixture_max = 1.89V
R_fixture = 45Ohm
C_fixture = 0F
|   Time   V(typ)   V(min)   V(max)
0s        1.301V     1.298V     1.285V
2.314ns   918.6mV    1.105V     697.4mV
2.469ns   -835.8mV   -783.1mV   -627.2mV
2.76ns    -5.303V    -8.683V    -3.101V
2.939ns   -6.691V    -11.71V    -3.728V
3.673ns   -7.641V    -14.66V    -3.27V
4.375ns   -6.136V    -11.53V    -3.025V
8.583ns   -6.04V     -11.55V    -2.666V
9.185ns   -539.1mV   -2.487V    562.9mV
9.9ns     895mV      947.6mV    856.5mV
[Falling Waveform]
|Gnd
V_fixture = 0V
V_fixture_min = 0V
V_fixture_max = 0V
R_fixture = 45Ohm
C_fixture = 0F
|   Time   V(typ)   V(min)   V(max)
0s        224.9mV    133mV      352.5mV
2.267ns   228.5mV    135.9mV    355.1mV
2.474ns   -59.44mV   -60.13mV   -710.3mV
2.774ns   -976.8mV   -1.207V    -2.477V
3.344ns   -1.352V    -1.714V    -3.022V
4.418ns   -1.139V    -1.489V    -2.504V
8.445ns   -1.054V    -1.358V    -2.342V
9.034ns   180.2mV    10.71mV    390.8mV
9.613ns   424.5mV    338.8mV    857mV
9.9ns     459.5mV    400.3mV    553.4mV
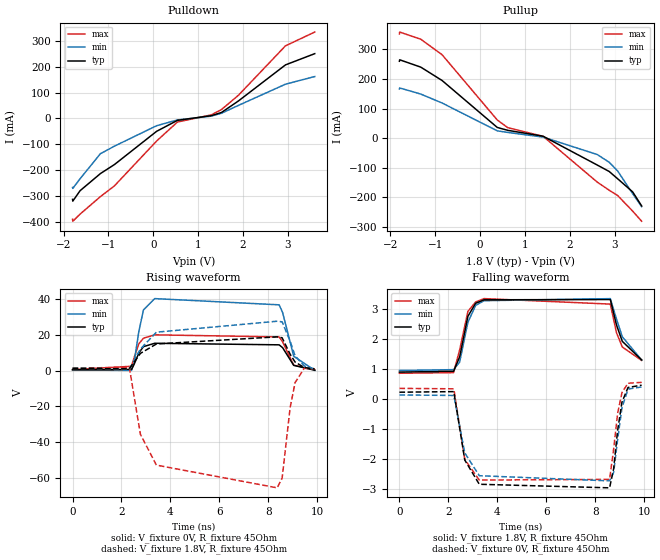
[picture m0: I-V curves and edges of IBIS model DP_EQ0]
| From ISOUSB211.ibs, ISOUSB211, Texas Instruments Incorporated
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[Model]   DP_EQ0
Model_type   Output
Polarity   Non-Inverting
Vmeas = 0.2
Vref = 0
Cref = 15pF
Rref = 45
|   typ   min   max
C_comp   5pF   3pF   8pF
[Voltage Range]   1.8   1.71   1.89
[Temperature Range]   27   150   -40
[Pullup Reference]   1.8   1.71   1.89
[Pulldown Reference]   0   0   0
[Power Clamp Reference]   1.8   1.71   1.89
[GND Clamp Reference]   0   0   0
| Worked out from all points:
|   slope of the pulldown table from 0 to 0.27 V, typ, clamps not added: 7.95 ohm
|   slope of the pullup table from 0 to 0.27 V, typ, clamps not added: 7.94 ohm
|   falling waveform, V_fixture 1.8V, R_fixture 45Ohm: 20-80 % time 105ps typ, 111ps min, 98.2ps max; typ from 0.895 V to 1.3 V
|   rising waveform, V_fixture 0V, R_fixture 45Ohm: 20-80 % time 88.5ps typ, 1.17ns min, 103ps max; typ from 0.46 V to 0.225 V
|   rising waveform, V_fixture 1.8V, R_fixture 45Ohm: 20-80 % time 125ps typ, 1.14ns min, 7.56ps max; typ from 1.3 V to 0.895 V
|   falling waveform, V_fixture 0V, R_fixture 45Ohm: 20-80 % time 129ps typ, 110ps min, 129ps max; typ from 0.225 V to 0.46 V
[Pulldown]
|   Voltage   I(typ)   I(min)   I(max)
-1.8V     -312.3mA   -266.2mA   -388.8mA
-1.795V   -319mA     -269.8mA   -396.8mA
-1.633V   -278.9mA   -232.8mA   -369.2mA
-1.179V   -212.7mA   -136mA     -301.6mA
-865.8mV  -177.8mA   -106.8mA   -260mA
73.8mV    -49.63mA   -27.98mA   -87.09mA
538.2mV   -7.266mA   -5.626mA   -13.71mA
1.294V    10.85mA    9.019mA    13.98mA
1.521V    23.18mA    20.15mA    34.45mA
1.899V    67.71mA    50.57mA    89.7mA
2.947V    206.8mA    132.3mA    280.4mA
3.6V      250.2mA    161.9mA    333.6mA
[Pullup]
|   Voltage   I(typ)   I(min)   I(max)
-1.8V     259.8mA    166.3mA    352.1mA
-1.795V   264.8mA    169.7mA    358.5mA
-1.325V   240.1mA    149.1mA    334.3mA
-849.6mV  194.9mA    118.9mA    282mA
381.6mV   36.3mA     24.84mA    61.51mA
613.8mV   26.64mA    19.55mA    35.63mA
1.402V    6.733mA    3.773mA    6.537mA
2.612V    -90.76mA   -55.24mA   -148.5mA
2.876V    -112.3mA   -81.28mA   -175.5mA
3.065V    -136.9mA   -110.7mA   -193.6mA
3.4V      -181.3mA   -187.3mA   -246.2mA
3.6V      -228.6mA   -231.2mA   -280.5mA
[Ramp]
R_load = 45
|   typ   min   max
dV/dt_r   0.140808/6.95986e-09   0.160407/4.91837e-09   0.120509/7.98955e-11
dV/dt_f   0.243789/9.43235e-11   0.210518/9.85826e-11   0.256824/9.07737e-11
[Falling Waveform]
V_fixture = 1.8V
V_fixture_min = 1.71V
V_fixture_max = 1.89V
R_fixture = 45Ohm
C_fixture = 0F
|   Time   V(typ)   V(min)   V(max)
0s        895mV      947.6mV    856.5mV
2.213ns   922.2mV    976.6mV    876.5mV
2.463ns   1.406V     1.233V     1.639V
2.799ns   2.755V     2.556V     2.919V
3.116ns   3.189V     3.118V     3.234V
3.459ns   3.304V     3.274V     3.344V
8.62ns    3.313V     3.343V     3.161V
8.872ns   2.465V     2.663V     2.207V
9.11ns    1.919V     2.071V     1.731V
9.9ns     1.301V     1.298V     1.285V
[Rising Waveform]
V_fixture = 0V
V_fixture_min = 0V
V_fixture_max = 0V
R_fixture = 45Ohm
C_fixture = 0F
|   Time   V(typ)   V(min)   V(max)
0s        459.5mV    400.3mV    553.4mV
2.408ns   652.2mV    69.85mV    2.437V
2.514ns   3.411V     4.527V     7.163V
2.708ns   9.87V      21.81V     15.02V
2.897ns   13.43V     33.96V     18.17V
3.357ns   15.32V     40.35V     20.05V
8.443ns   14.45V     36.86V     18.87V
8.584ns   12.88V     32.64V     16.16V
9.04ns    2.938V     8.042V     3.048V
9.9ns     224.9mV    133mV      352.5mV
[Rising Waveform]
V_fixture = 1.8V
V_fixture_min = 1.71V
V_fixture_max = 1.89V
R_fixture = 45Ohm
C_fixture = 0F
|   Time   V(typ)   V(min)   V(max)
0s        1.301V     1.298V     1.285V
2.319ns   1.048V     871.4mV    1.941V
2.774ns   9.673V     12.13V     -35.72V
3.427ns   14.93V     21.53V     -52.94V
8.364ns   18.92V     27.68V     -65.68V
8.566ns   18.4V      27.33V     -60.26V
8.894ns   9.164V     16.45V     -20.65V
9.095ns   4.813V     8.275V     -6.748V
9.471ns   1.731V     2.627V     1.308V
9.9ns     895mV      947.6mV    856.5mV
[Falling Waveform]
|Gnd
V_fixture = 0V
V_fixture_min = 0V
V_fixture_max = 0V
R_fixture = 45Ohm
C_fixture = 0F
|   Time   V(typ)   V(min)   V(max)
0s        224.9mV    133mV      352.5mV
2.223ns   244.1mV    116.3mV    337.8mV
2.671ns   -2.036V    -1.798V    -2.017V
3.264ns   -2.843V    -2.558V    -2.703V
8.59ns    -2.962V    -2.73V     -2.681V
8.755ns   -2.33V     -2.449V    -1.681V
8.916ns   -1.067V    -1.374V    -493.3mV
9.095ns   -111.3mV   -294.7mV   210.1mV
9.343ns   382.7mV    328.6mV    523.5mV
9.9ns     459.5mV    400.3mV    553.4mV
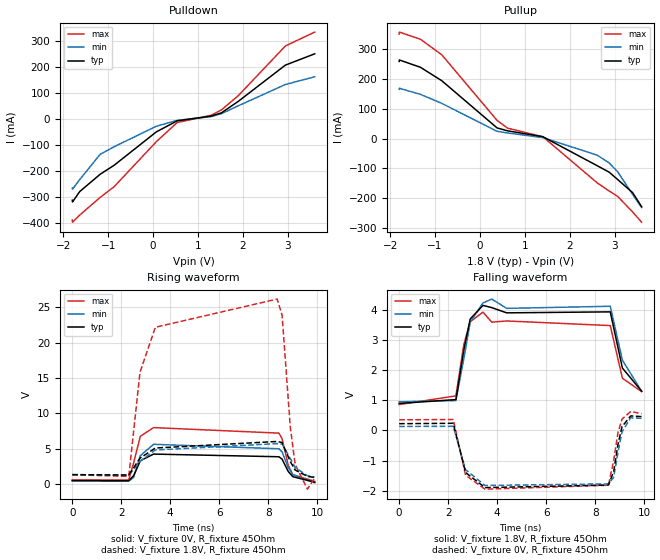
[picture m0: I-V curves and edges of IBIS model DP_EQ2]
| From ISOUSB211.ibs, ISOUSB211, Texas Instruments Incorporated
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[Model]   DP_EQ2
Model_type   Output
Polarity   Non-Inverting
Vmeas = 0.2
Vref = 0
Cref = 15pF
Rref = 45
|   typ   min   max
C_comp   5pF   3pF   8pF
[Voltage Range]   1.8   1.71   1.89
[Temperature Range]   27   150   -40
[Pullup Reference]   1.8   1.71   1.89
[Pulldown Reference]   0   0   0
[Power Clamp Reference]   1.8   1.71   1.89
[GND Clamp Reference]   0   0   0
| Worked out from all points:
|   slope of the pulldown table from 0 to 0.27 V, typ, clamps not added: 7.95 ohm
|   slope of the pullup table from 0 to 0.27 V, typ, clamps not added: 7.94 ohm
|   falling waveform, V_fixture 1.8V, R_fixture 45Ohm: 20-80 % time 90.1ps typ, 93.9ps min, 89ps max; typ from 0.895 V to 1.3 V
|   rising waveform, V_fixture 0V, R_fixture 45Ohm: 20-80 % time 361ps typ, 262ps min, 73.4ps max; typ from 0.46 V to 0.225 V
|   rising waveform, V_fixture 1.8V, R_fixture 45Ohm: 20-80 % time 353ps typ, 320ps min, 30.5ps max; typ from 1.3 V to 0.895 V
|   falling waveform, V_fixture 0V, R_fixture 45Ohm: 20-80 % time 134ps typ, 143ps min, 99.3ps max; typ from 0.225 V to 0.46 V
[Pulldown]
|   Voltage   I(typ)   I(min)   I(max)
-1.8V     -312.3mA   -266.2mA   -388.8mA
-1.795V   -319mA     -269.8mA   -396.8mA
-1.633V   -278.9mA   -232.8mA   -369.2mA
-1.179V   -212.7mA   -136mA     -301.6mA
-865.8mV  -177.8mA   -106.8mA   -260mA
73.8mV    -49.63mA   -27.98mA   -87.09mA
538.2mV   -7.266mA   -5.626mA   -13.71mA
1.294V    10.85mA    9.019mA    13.98mA
1.521V    23.18mA    20.15mA    34.45mA
1.899V    67.71mA    50.57mA    89.7mA
2.947V    206.8mA    132.3mA    280.4mA
3.6V      250.2mA    161.9mA    333.6mA
[Pullup]
|   Voltage   I(typ)   I(min)   I(max)
-1.8V     259.8mA    166.3mA    352.1mA
-1.795V   264.8mA    169.7mA    358.5mA
-1.325V   240.1mA    149.1mA    334.3mA
-849.6mV  194.9mA    118.9mA    282mA
381.6mV   36.3mA     24.84mA    61.51mA
613.8mV   26.64mA    19.55mA    35.63mA
1.402V    6.733mA    3.773mA    6.537mA
2.612V    -90.76mA   -55.24mA   -148.5mA
2.876V    -112.3mA   -81.28mA   -175.5mA
3.065V    -136.9mA   -110.7mA   -193.6mA
3.4V      -181.3mA   -187.3mA   -246.2mA
3.6V      -228.6mA   -231.2mA   -280.5mA
[Ramp]
R_load = 45
|   typ   min   max
dV/dt_r   0.140808/6.69265e-09   0.160407/7.37501e-09   0.120509/7.04513e-09
dV/dt_f   0.243789/8.30855e-11   0.210518/8.76888e-11   0.256824/8.16326e-11
[Falling Waveform]
V_fixture = 1.8V
V_fixture_min = 1.71V
V_fixture_max = 1.89V
R_fixture = 45Ohm
C_fixture = 0F
|   Time   V(typ)   V(min)   V(max)
0s        895mV      947.6mV    856.5mV
2.317ns   1.021V     989.8mV    1.145V
2.64ns    2.664V     2.372V     2.844V
2.901ns   3.686V     3.578V     3.594V
3.421ns   4.137V     4.217V     3.913V
3.783ns   4.063V     4.346V     3.582V
4.388ns   3.89V      4.038V     3.622V
8.62ns    3.923V     4.108V     3.469V
9.115ns   2.064V     2.325V     1.728V
9.9ns     1.301V     1.298V     1.285V
[Rising Waveform]
V_fixture = 0V
V_fixture_min = 0V
V_fixture_max = 0V
R_fixture = 45Ohm
C_fixture = 0F
|   Time   V(typ)   V(min)   V(max)
0s        459.5mV    400.3mV    553.4mV
2.302ns   434.1mV    371.4mV    521.5mV
2.503ns   1.141V     905.3mV    2.945V
2.779ns   3.269V     3.991V     6.74V
3.32ns    4.214V     5.6V       7.968V
8.436ns   3.836V     4.969V     7.185V
8.565ns   3.505V     4.527V     6.4V
8.819ns   1.744V     2.304V     2.609V
9.004ns   1.009V     1.309V     1.301V
9.9ns     224.9mV    133mV      352.5mV
[Rising Waveform]
V_fixture = 1.8V
V_fixture_min = 1.71V
V_fixture_max = 1.89V
R_fixture = 45Ohm
C_fixture = 0F
|   Time   V(typ)   V(min)   V(max)
0s        1.301V     1.298V     1.285V
2.306ns   1.243V     1.233V     1.046V
2.765ns   3.635V     3.173V     15.81V
3.392ns   5.073V     4.79V      22.19V
8.363ns   6.003V     5.701V     26.19V
8.565ns   5.847V     5.639V     23.95V
8.901ns   3.163V     3.591V     8.049V
9.1ns     1.96V      2.303V     2.738V
9.602ns   1.054V     1.143V     -759.2mV
9.9ns     895mV      947.6mV    856.5mV
[Falling Waveform]
|Gnd
V_fixture = 0V
V_fixture_min = 0V
V_fixture_max = 0V
R_fixture = 45Ohm
C_fixture = 0F
|   Time   V(typ)   V(min)   V(max)
0s        224.9mV    133mV      352.5mV
2.207ns   237.7mV    137.2mV    363mV
2.713ns   -1.392V    -1.296V    -1.48V
3.504ns   -1.889V    -1.818V    -1.941V
8.545ns   -1.805V    -1.765V    -1.811V
8.758ns   -1.362V    -1.55V     -992.3mV
8.934ns   -461mV     -724.8mV   -73.04mV
9.1ns     127.4mV    -45.79mV   374.4mV
9.456ns   481.9mV    418.7mV    628.7mV
9.9ns     459.5mV    400.3mV    553.4mV
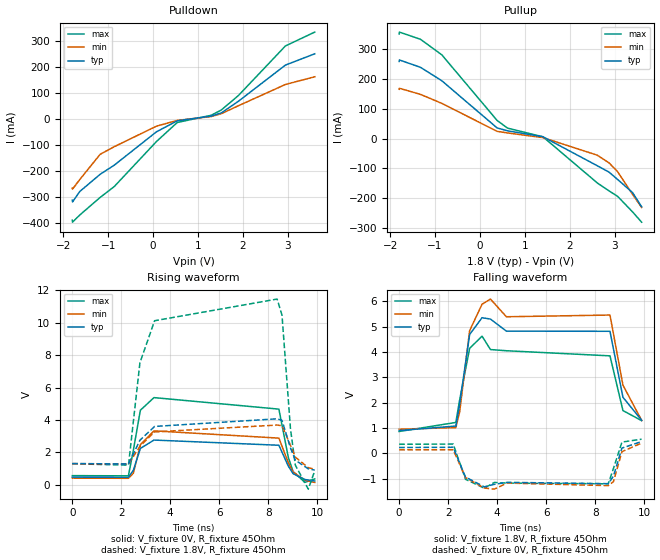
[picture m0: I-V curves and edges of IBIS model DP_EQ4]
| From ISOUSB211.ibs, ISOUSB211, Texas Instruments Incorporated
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[Model]   DP_EQ4
Model_type   Output
Polarity   Non-Inverting
Vmeas = 0.2
Vref = 0
Cref = 15pF
Rref = 45
|   typ   min   max
C_comp   5pF   3pF   8pF
[Voltage Range]   1.8   1.71   1.89
[Temperature Range]   27   150   -40
[Pullup Reference]   1.8   1.71   1.89
[Pulldown Reference]   0   0   0
[Power Clamp Reference]   1.8   1.71   1.89
[GND Clamp Reference]   0   0   0
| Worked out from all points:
|   slope of the pulldown table from 0 to 0.27 V, typ, clamps not added: 7.95 ohm
|   slope of the pullup table from 0 to 0.27 V, typ, clamps not added: 7.94 ohm
|   falling waveform, V_fixture 1.8V, R_fixture 45Ohm: 20-80 % time 79ps typ, 76.1ps min, 80.7ps max; typ from 0.895 V to 1.3 V
|   rising waveform, V_fixture 0V, R_fixture 45Ohm: 20-80 % time 393ps typ, 397ps min, 60ps max; typ from 0.46 V to 0.225 V
|   rising waveform, V_fixture 1.8V, R_fixture 45Ohm: 20-80 % time 344ps typ, 347ps min, 42.2ps max; typ from 1.3 V to 0.895 V
|   falling waveform, V_fixture 0V, R_fixture 45Ohm: 20-80 % time 162ps typ, 173ps min, 102ps max; typ from 0.225 V to 0.46 V
[Pulldown]
|   Voltage   I(typ)   I(min)   I(max)
-1.8V     -312.3mA   -266.2mA   -388.8mA
-1.795V   -319mA     -269.8mA   -396.8mA
-1.633V   -278.9mA   -232.8mA   -369.2mA
-1.179V   -212.7mA   -136mA     -301.6mA
-865.8mV  -177.8mA   -106.8mA   -260mA
73.8mV    -49.63mA   -27.98mA   -87.09mA
538.2mV   -7.266mA   -5.626mA   -13.71mA
1.294V    10.85mA    9.019mA    13.98mA
1.521V    23.18mA    20.15mA    34.45mA
1.899V    67.71mA    50.57mA    89.7mA
2.947V    206.8mA    132.3mA    280.4mA
3.6V      250.2mA    161.9mA    333.6mA
[Pullup]
|   Voltage   I(typ)   I(min)   I(max)
-1.8V     259.8mA    166.3mA    352.1mA
-1.795V   264.8mA    169.7mA    358.5mA
-1.325V   240.1mA    149.1mA    334.3mA
-849.6mV  194.9mA    118.9mA    282mA
381.6mV   36.3mA     24.84mA    61.51mA
613.8mV   26.64mA    19.55mA    35.63mA
1.402V    6.733mA    3.773mA    6.537mA
2.612V    -90.76mA   -55.24mA   -148.5mA
2.876V    -112.3mA   -81.28mA   -175.5mA
3.065V    -136.9mA   -110.7mA   -193.6mA
3.4V      -181.3mA   -187.3mA   -246.2mA
3.6V      -228.6mA   -231.2mA   -280.5mA
[Ramp]
R_load = 45
|   typ   min   max
dV/dt_r   0.140808/3.20106e-10   0.160407/3.14772e-10   0.120509/5.97636e-09
dV/dt_f   0.243789/7.35768e-11   0.210518/7.76904e-11   0.256824/7.51741e-09
[Falling Waveform]
V_fixture = 1.8V
V_fixture_min = 1.71V
V_fixture_max = 1.89V
R_fixture = 45Ohm
C_fixture = 0F
|   Time   V(typ)   V(min)   V(max)
0s        895mV      947.6mV    856.5mV
2.315ns   1.072V     1.01V      1.214V
2.47ns    1.938V     1.626V     2.103V
2.878ns   4.689V     4.84V      4.14V
3.385ns   5.35V      5.883V     4.622V
3.728ns   5.297V     6.087V     4.093V
4.378ns   4.82V      5.388V     4.046V
8.608ns   4.814V     5.456V     3.844V
9.137ns   2.208V     2.687V     1.684V
9.9ns     1.301V     1.298V     1.285V
[Rising Waveform]
V_fixture = 0V
V_fixture_min = 0V
V_fixture_max = 0V
R_fixture = 45Ohm
C_fixture = 0F
|   Time   V(typ)   V(min)   V(max)
0s        459.5mV    400.3mV    553.4mV
2.291ns   449.5mV    388.7mV    542mV
2.496ns   890.4mV    709.3mV    2.14V
2.78ns    2.234V     2.471V     4.597V
3.336ns   2.753V     3.322V     5.378V
8.436ns   2.432V     2.873V     4.665V
8.821ns   1.142V     1.356V     1.68V
9.016ns   675.5mV    778.5mV    803.6mV
9.495ns   314.6mV    271.5mV    138.3mV
9.9ns     224.9mV    133mV      352.5mV
[Rising Waveform]
V_fixture = 1.8V
V_fixture_min = 1.71V
V_fixture_max = 1.89V
R_fixture = 45Ohm
C_fixture = 0F
|   Time   V(typ)   V(min)   V(max)
0s        1.301V     1.298V     1.285V
2.295ns   1.274V     1.27V      1.204V
2.762ns   2.744V     2.369V     7.532V
3.361ns   3.595V     3.257V     10.13V
8.364ns   4.067V     3.681V     11.47V
8.563ns   3.969V     3.639V     10.47V
8.908ns   2.272V     2.437V     3.469V
9.107ns   1.514V     1.698V     1.203V
9.636ns   972.5mV    1.048V     -282.8mV
9.9ns     895mV      947.6mV    856.5mV
[Falling Waveform]
|Gnd
V_fixture = 0V
V_fixture_min = 0V
V_fixture_max = 0V
R_fixture = 45Ohm
C_fixture = 0F
|   Time   V(typ)   V(min)   V(max)
0s        224.9mV    133mV      352.5mV
2.207ns   233.9mV    136.1mV    359.9mV
2.708ns   -942.2mV   -960.6mV   -1.03V
3.475ns   -1.329V    -1.376V    -1.383V
3.885ns   -1.23V     -1.421V    -1.156V
4.401ns   -1.152V    -1.18V     -1.182V
8.537ns   -1.204V    -1.281V    -1.21V
8.75ns    -904.2mV   -1.123V    -604mV
9.095ns   201.5mV    57.58mV    437.8mV
9.9ns     459.5mV    400.3mV    553.4mV
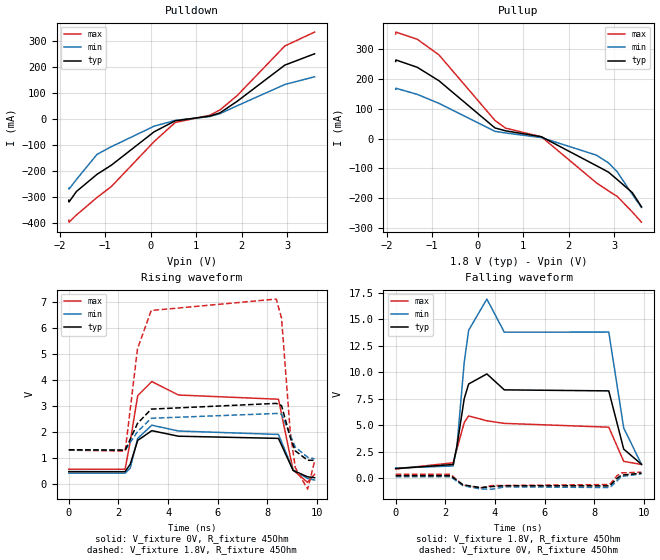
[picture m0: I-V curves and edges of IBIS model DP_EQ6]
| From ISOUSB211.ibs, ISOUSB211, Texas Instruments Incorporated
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[Model]   DP_EQ6
Model_type   Output
Polarity   Non-Inverting
Vmeas = 0.2
Vref = 0
Cref = 15pF
Rref = 45
|   typ   min   max
C_comp   5pF   3pF   8pF
[Voltage Range]   1.8   1.71   1.89
[Temperature Range]   27   150   -40
[Pullup Reference]   1.8   1.71   1.89
[Pulldown Reference]   0   0   0
[Power Clamp Reference]   1.8   1.71   1.89
[GND Clamp Reference]   0   0   0
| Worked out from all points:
|   slope of the pulldown table from 0 to 0.27 V, typ, clamps not added: 7.95 ohm
|   slope of the pullup table from 0 to 0.27 V, typ, clamps not added: 7.94 ohm
|   falling waveform, V_fixture 1.8V, R_fixture 45Ohm: 20-80 % time 220ps typ, 96.7ps min, 53.4ps max; typ from 0.895 V to 1.3 V
|   rising waveform, V_fixture 0V, R_fixture 45Ohm: 20-80 % time 334ps typ, 403ps min, 68.7ps max; typ from 0.46 V to 0.225 V
|   rising waveform, V_fixture 1.8V, R_fixture 45Ohm: 20-80 % time 278ps typ, 368ps min, 46.9ps max; typ from 1.3 V to 0.895 V
|   falling waveform, V_fixture 0V, R_fixture 45Ohm: 20-80 % time 205ps typ, 207ps min, 115ps max; typ from 0.225 V to 0.46 V
[Pulldown]
|   Voltage   I(typ)   I(min)   I(max)
-1.8V     -312.3mA   -266.2mA   -388.8mA
-1.795V   -319mA     -269.8mA   -396.8mA
-1.633V   -278.9mA   -232.8mA   -369.2mA
-1.179V   -212.7mA   -136mA     -301.6mA
-865.8mV  -177.8mA   -106.8mA   -260mA
73.8mV    -49.63mA   -27.98mA   -87.09mA
538.2mV   -7.266mA   -5.626mA   -13.71mA
1.294V    10.85mA    9.019mA    13.98mA
1.521V    23.18mA    20.15mA    34.45mA
1.899V    67.71mA    50.57mA    89.7mA
2.947V    206.8mA    132.3mA    280.4mA
3.6V      250.2mA    161.9mA    333.6mA
[Pullup]
|   Voltage   I(typ)   I(min)   I(max)
-1.8V     259.8mA    166.3mA    352.1mA
-1.795V   264.8mA    169.7mA    358.5mA
-1.325V   240.1mA    149.1mA    334.3mA
-849.6mV  194.9mA    118.9mA    282mA
381.6mV   36.3mA     24.84mA    61.51mA
613.8mV   26.64mA    19.55mA    35.63mA
1.402V    6.733mA    3.773mA    6.537mA
2.612V    -90.76mA   -55.24mA   -148.5mA
2.876V    -112.3mA   -81.28mA   -175.5mA
3.065V    -136.9mA   -110.7mA   -193.6mA
3.4V      -181.3mA   -187.3mA   -246.2mA
3.6V      -228.6mA   -231.2mA   -280.5mA
[Ramp]
R_load = 45
|   typ   min   max
dV/dt_r   0.140808/3.03725e-10   0.160407/3.44966e-10   0.120509/6.8636e-11
dV/dt_f   0.243789/5.79501e-11   0.210518/5.77407e-11   0.256824/7.18882e-09
[Falling Waveform]
V_fixture = 1.8V
V_fixture_min = 1.71V
V_fixture_max = 1.89V
R_fixture = 45Ohm
C_fixture = 0F
|   Time   V(typ)   V(min)   V(max)
0s        895mV      947.6mV    856.5mV
2.314ns   1.278V     1.141V     1.444V
2.469ns   3.032V     3.029V     2.768V
2.76ns    7.499V     10.93V     5.242V
2.939ns   8.888V     13.96V     5.869V
3.673ns   9.837V     16.91V     5.411V
4.375ns   8.332V     13.78V     5.166V
8.583ns   8.236V     13.79V     4.807V
9.185ns   2.735V     4.733V     1.578V
9.9ns     1.301V     1.298V     1.285V
[Rising Waveform]
V_fixture = 0V
V_fixture_min = 0V
V_fixture_max = 0V
R_fixture = 45Ohm
C_fixture = 0F
|   Time   V(typ)   V(min)   V(max)
0s        459.5mV    400.3mV    553.4mV
2.267ns   455.9mV    397.5mV    550.8mV
2.474ns   743.8mV    593.4mV    1.616V
2.774ns   1.661V     1.741V     3.383V
3.344ns   2.036V     2.247V     3.928V
4.418ns   1.823V     2.023V     3.41V
8.445ns   1.739V     1.891V     3.248V
9.034ns   504.2mV    522.6mV    515.1mV
9.613ns   259.8mV    194.5mV    48.86mV
9.9ns     224.9mV    133mV      352.5mV
[Rising Waveform]
V_fixture = 1.8V
V_fixture_min = 1.71V
V_fixture_max = 1.89V
R_fixture = 45Ohm
C_fixture = 0F
|   Time   V(typ)   V(min)   V(max)
0s        1.301V     1.298V     1.285V
2.271ns   1.287V     1.287V     1.25V
2.767ns   2.317V     1.998V     5.194V
3.32ns    2.867V     2.514V     6.668V
8.356ns   3.088V     2.699V     7.108V
8.569ns   3.001V     2.671V     6.373V
8.92ns    1.778V     1.865V     1.988V
9.122ns   1.257V     1.401V     611.6mV
9.62ns    896.3mV    1.012V     -217.7mV
9.9ns     895mV      947.6mV    856.5mV
[Falling Waveform]
|Gnd
V_fixture = 0V
V_fixture_min = 0V
V_fixture_max = 0V
R_fixture = 45Ohm
C_fixture = 0F
|   Time   V(typ)   V(min)   V(max)
0s        224.9mV    133mV      352.5mV
2.207ns   230.7mV    135.2mV    357.3mV
2.708ns   -631.6mV   -716.4mV   -666.4mV
3.43ns    -910.9mV   -1.036V    -924.7mV
3.896ns   -797.2mV   -1.049V    -703.6mV
4.4ns     -721.3mV   -827.8mV   -706mV
8.62ns    -736.6mV   -894.8mV   -610mV
8.92ns    -28.64mV   -263.2mV   231.1mV
9.094ns   274.9mV    152.6mV    486mV
9.9ns     459.5mV    400.3mV    553.4mV
